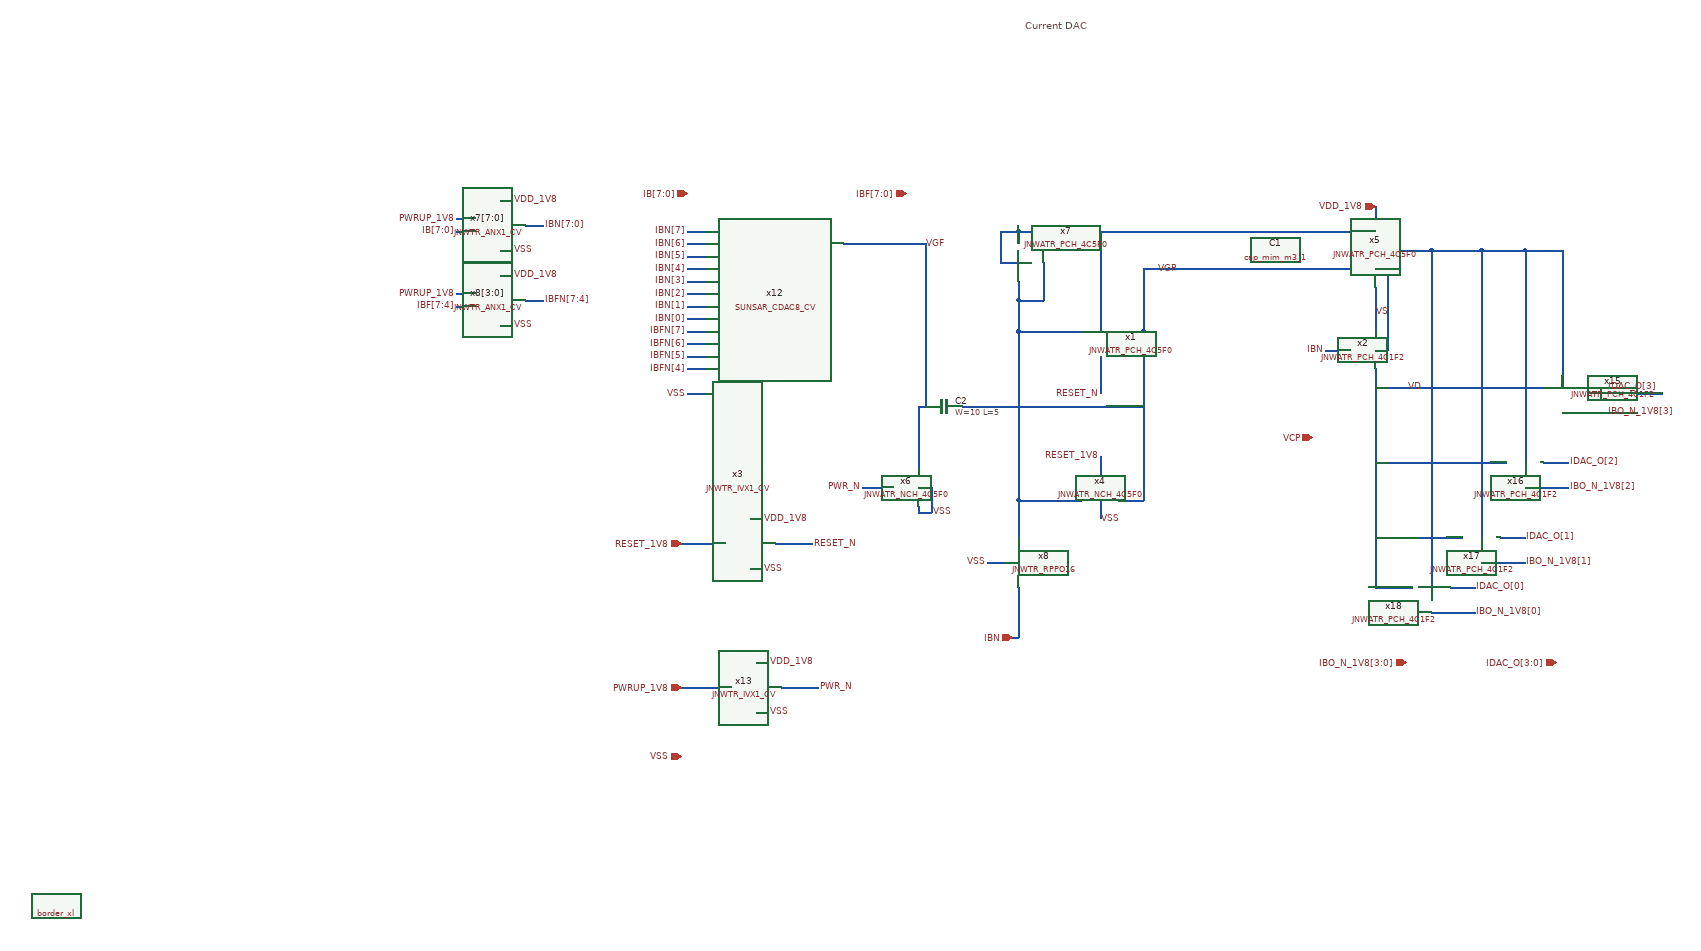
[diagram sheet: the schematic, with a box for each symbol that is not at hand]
v {xschem version=3.4.5 file_version=1.2
}
G {}
K {}
V {}
S {}
E {}
T {Current DAC} 1740 -1640 0 0 0.5 0.5 {}
N 2300 -1210 2300 -1140 {
lab=VS}
N 2300 -1110 2320 -1110 {
lab=VDD_1V8}
N 2320 -1240 2320 -1110 {
lab=VDD_1V8}
N 2300 -1240 2320 -1240 {
lab=VDD_1V8}
N 2320 -1270 2320 -1240 {
lab=VDD_1V8}
N 2300 -1270 2320 -1270 {
lab=VDD_1V8}
N 2300 -1330 2300 -1270 {
lab=VDD_1V8}
N 1930 -1240 2260 -1240 {
lab=VGP}
N 2300 -1080 2300 -900 {
lab=VD}
N 1310 -610 1330 -610 {
lab=VDD_1V8}
N 1310 -530 1330 -530 {
lab=VSS}
N 1250 -570 1270 -570 {
lab=PWRUP_1V8}
N 1190 -570 1250 -570 {
lab=PWRUP_1V8}
N 1350 -570 1410 -570 {
lab=PWR_N}
N 2390 -1270 2390 -730 {
lab=VDD_1V8}
N 2320 -1270 2390 -1270 {
lab=VDD_1V8}
N 2470 -1270 2470 -810 {
lab=VDD_1V8}
N 2390 -1270 2470 -1270 {
lab=VDD_1V8}
N 2470 -1270 2540 -1270 {
lab=VDD_1V8}
N 2600 -1270 2600 -1050 {
lab=VDD_1V8}
N 2540 -1270 2600 -1270 {
lab=VDD_1V8}
N 2300 -1050 2570 -1050 {
lab=VD}
N 2300 -900 2300 -730 {
lab=VD}
N 2300 -730 2360 -730 {
lab=VD}
N 2300 -810 2440 -810 {
lab=VD}
N 2300 -930 2510 -930 {
lab=VD}
N 2540 -1270 2540 -930 {
lab=VDD_1V8}
N 2630 -1050 2670 -1050 {
lab=IDAC_O[3]}
N 2570 -930 2610 -930 {
lab=IDAC_O[2]}
N 2500 -810 2540 -810 {
lab=IDAC_O[1]}
N 2420 -730 2460 -730 {
lab=IDAC_O[0]}
N 2390 -690 2460 -690 {
lab=IBO_N_1V8[0]}
N 2470 -770 2540 -770 {
lab=IBO_N_1V8[1]}
N 2540 -890 2610 -890 {
lab=IBO_N_1V8[2]}
N 2600 -1010 2670 -1010 {
lab=IBO_N_1V8[3]}
N 1200 -1160 1230 -1160 {
lab=IBN[0]}
N 1200 -1180 1230 -1180 {
lab=IBN[1]}
N 1200 -1200 1230 -1200 {
lab=IBN[2]}
N 1200 -1220 1230 -1220 {
lab=IBN[3]}
N 1200 -1240 1230 -1240 {
lab=IBN[4]}
N 1200 -1260 1230 -1260 {
lab=IBN[5]}
N 1200 -1280 1230 -1280 {
lab=IBN[6]}
N 1200 -1300 1230 -1300 {
lab=IBN[7]}
N 1450 -1280 1480 -1280 {
lab=VGF}
N 1200 -1040 1230 -1040 {
lab=VSS}
N 2660 -1040 2760 -1040 {
lab=IDAC_O[3]}
N 2660 -1050 2660 -1040 {
lab=IDAC_O[3]}
N 2300 -1340 2300 -1330 {
lab=VDD_1V8}
N 2220 -1110 2260 -1110 {
lab=IBN}
N 1200 -1140 1230 -1140 {
lab=IBFN[7]}
N 1200 -1120 1230 -1120 {
lab=IBFN[6]}
N 1200 -1100 1230 -1100 {
lab=IBFN[5]}
N 1200 -1080 1230 -1080 {
lab=IBFN[4]}
N 1730 -1220 1730 -1190 {
lab=#net1}
N 1730 -1190 1770 -1190 {
lab=#net1}
N 1770 -1250 1770 -1190 {
lab=#net1}
N 1700 -1250 1730 -1250 {
lab=VDD_1V8}
N 1700 -1300 1700 -1250 {
lab=VDD_1V8}
N 1700 -1300 1730 -1300 {
lab=VDD_1V8}
N 1730 -1300 1730 -1280 {
lab=VDD_1V8}
N 1730 -1300 2300 -1300 {
lab=VDD_1V8}
N 1720 -650 1730 -650 {
lab=IBN}
N 1240 -800 1260 -800 {
lab=RESET_1V8}
N 1190 -800 1240 -800 {
lab=RESET_1V8}
N 1340 -800 1400 -800 {
lab=RESET_N}
N 1860 -1300 1860 -1140 {
lab=VDD_1V8}
N 1730 -1140 1830 -1140 {
lab=#net1}
N 1890 -1140 1930 -1140 {
lab=VGP}
N 1930 -1240 1930 -1140 {
lab=VGP}
N 1860 -1100 1860 -1040 {
lab=RESET_N}
N 1300 -840 1320 -840 {
lab=VDD_1V8}
N 1300 -760 1320 -760 {
lab=VSS}
N 1860 -870 1860 -840 {
lab=VSS}
N 1890 -870 1930 -870 {
lab=VGP}
N 1930 -1140 1930 -870 {
lab=VGP}
N 1730 -870 1830 -870 {
lab=#net1}
N 1860 -940 1860 -910 {
lab=RESET_1V8}
N 1640 -1020 1930 -1020 {
lab=VGP}
N 1580 -1280 1580 -1020 {
lab=VGF}
N 1480 -1280 1580 -1280 {
lab=VGF}
N 1480 -890 1530 -890 {
lab=PWR_N}
N 1570 -1020 1570 -920 {
lab=VGF}
N 1570 -1020 1580 -1020 {
lab=VGF}
N 1570 -890 1590 -890 {
lab=VSS}
N 1590 -890 1590 -850 {
lab=VSS}
N 1570 -850 1590 -850 {
lab=VSS}
N 1570 -860 1570 -850 {
lab=VSS}
N 900 -1270 920 -1270 {
lab=VSS}
N 900 -1350 920 -1350 {
lab=VDD_1V8}
N 940 -1310 970 -1310 {
lab=IBN[7:0]}
N 830 -1300 860 -1300 {
lab=IB[7:0]}
N 900 -1150 920 -1150 {
lab=VSS}
N 900 -1230 920 -1230 {
lab=VDD_1V8}
N 940 -1190 970 -1190 {
lab=IBFN[7:4]}
N 830 -1180 860 -1180 {
lab=IBF[7:4]}
N 830 -1320 860 -1320 {
lab=PWRUP_1V8}
N 830 -1200 860 -1200 {
lab=PWRUP_1V8}
N 1730 -1140 1730 -1120 {
lab=#net1}
N 1730 -1190 1730 -1140 {
lab=#net1}
N 1730 -1120 1730 -870 {
lab=#net1}
N 1730 -870 1730 -810 {
lab=#net1}
N 1730 -730 1730 -650 {
lab=IBN}
N 1680 -770 1710 -770 {
lab=VSS}
C {devices/ipin.sym} 2300 -1340 0 0 {name=p1 lab=VDD_1V8}
C {devices/ipin.sym} 1190 -460 0 0 {name=p2 lab=VSS}
C {devices/ipin.sym} 1190 -570 0 0 {name=p3 lab=PWRUP_1V8}
C {JNW_ATR_SKY130A/JNWATR_PCH_4C5F0.sym} 2260 -1240 0 0 {name=x5}
C {JNW_ATR_SKY130A/JNWATR_PCH_4C1F2.sym} 2260 -1110 0 0 {name=x2 }
C {JNW_TR_SKY130A/JNWTR_IVX1_CV.sym} 1270 -570 0 0 {name=x13 }
C {devices/lab_wire.sym} 1330 -610 0 1 {name=p29 sig_type=std_logic lab=VDD_1V8}
C {devices/lab_wire.sym} 1330 -530 0 1 {name=p30 sig_type=std_logic lab=VSS}
C {devices/lab_wire.sym} 1410 -570 0 1 {name=p33 sig_type=std_logic lab=PWR_N}
C {devices/iopin.sym} 2590 -610 0 0 {name=p35 lab=IDAC_O[3:0]}
C {JNW_ATR_SKY130A/JNWATR_PCH_4C1F2.sym} 2600 -1010 3 0 {name=x15 }
C {JNW_ATR_SKY130A/JNWATR_PCH_4C1F2.sym} 2540 -890 3 0 {name=x16 }
C {JNW_ATR_SKY130A/JNWATR_PCH_4C1F2.sym} 2470 -770 3 0 {name=x17 }
C {JNW_ATR_SKY130A/JNWATR_PCH_4C1F2.sym} 2390 -690 3 0 {name=x18 }
C {devices/lab_wire.sym} 2460 -730 0 1 {name=p36 sig_type=std_logic lab=IDAC_O[0]}
C {devices/lab_wire.sym} 2540 -810 0 1 {name=p37 sig_type=std_logic lab=IDAC_O[1]}
C {devices/lab_wire.sym} 2610 -930 0 1 {name=p38 sig_type=std_logic lab=IDAC_O[2]}
C {devices/lab_wire.sym} 2670 -1050 0 1 {name=p39 sig_type=std_logic lab=IDAC_O[3]}
C {devices/lab_wire.sym} 2460 -690 0 1 {name=p40 sig_type=std_logic lab=IBO_N_1V8[0]}
C {devices/lab_wire.sym} 2540 -770 0 1 {name=p41 sig_type=std_logic lab=IBO_N_1V8[1]}
C {devices/lab_wire.sym} 2610 -890 0 1 {name=p42 sig_type=std_logic lab=IBO_N_1V8[2]}
C {devices/lab_wire.sym} 2670 -1010 0 1 {name=p43 sig_type=std_logic lab=IBO_N_1V8[3]}
C {devices/ipin.sym} 1200 -1360 0 0 {name=p44 lab=IB[7:0]}
C {devices/ipin.sym} 2350 -610 0 0 {name=p45 lab=IBO_N_1V8[3:0]}
C {devices/lab_wire.sym} 2300 -1170 0 1 {name=p47 sig_type=std_logic lab=VS}
C {devices/lab_wire.sym} 2350 -1050 0 1 {name=p48 sig_type=std_logic lab=VD}
C {devices/lab_wire.sym} 1950 -1240 0 1 {name=p49 sig_type=std_logic lab=VGP}
C {devices/lab_wire.sym} 1200 -1160 0 0 {name=p46 sig_type=std_logic lab=IBN[0]
}
C {devices/lab_wire.sym} 1200 -1180 0 0 {name=p66 sig_type=std_logic lab=IBN[1]
}
C {devices/lab_wire.sym} 1200 -1200 0 0 {name=p67 sig_type=std_logic lab=IBN[2]
}
C {devices/lab_wire.sym} 1200 -1220 0 0 {name=p68 sig_type=std_logic lab=IBN[3]
}
C {devices/lab_wire.sym} 1200 -1240 0 0 {name=p69 sig_type=std_logic lab=IBN[4]
}
C {devices/lab_wire.sym} 1200 -1260 0 0 {name=p70 sig_type=std_logic lab=IBN[5]
}
C {devices/lab_wire.sym} 1200 -1280 0 0 {name=p71 sig_type=std_logic lab=IBN[6]
}
C {devices/lab_wire.sym} 1200 -1300 0 0 {name=p72 sig_type=std_logic lab=IBN[7]
}
C {devices/lab_wire.sym} 1200 -1040 0 0 {name=p74 sig_type=std_logic lab=VSS
}
C {SUN_SAR9B_SKY130NM/SUNSAR_CDAC8_CV.sym} 1250 -1300 0 0 {name=x12}
C {devices/ipin.sym} 1550 -1360 0 0 {name=p124 lab=IBF[7:0]}
C {devices/lab_wire.sym} 1200 -1140 0 0 {name=p4 sig_type=std_logic lab=IBFN[7]
}
C {devices/lab_wire.sym} 1200 -1120 0 0 {name=p5 sig_type=std_logic lab=IBFN[6]
}
C {devices/lab_wire.sym} 1200 -1100 0 0 {name=p6 sig_type=std_logic lab=IBFN[5]
}
C {devices/lab_wire.sym} 1200 -1080 0 0 {name=p7 sig_type=std_logic lab=IBFN[4]
}
C {devices/ipin.sym} 1720 -650 0 0 {name=p8 lab=IBN}
C {JNW_ATR_SKY130A/JNWATR_PCH_4C5F0.sym} 1770 -1250 0 1 {name=x7}
C {JNW_ATR_SKY130A/JNWATR_PCH_4C5F0.sym} 1860 -1100 3 0 {name=x1 }
C {devices/ipin.sym} 1190 -800 0 0 {name=p9 lab=RESET_1V8}
C {devices/lab_wire.sym} 1400 -800 0 1 {name=p12 sig_type=std_logic lab=RESET_N}
C {devices/lab_wire.sym} 1860 -1040 0 0 {name=p13 sig_type=std_logic lab=RESET_N}
C {JNW_TR_SKY130A/JNWTR_IVX1_CV.sym} 1260 -800 0 0 {name=x3 }
C {devices/lab_wire.sym} 1320 -840 0 1 {name=p10 sig_type=std_logic lab=VDD_1V8}
C {devices/lab_wire.sym} 1320 -760 0 1 {name=p11 sig_type=std_logic lab=VSS}
C {JNW_ATR_SKY130A/JNWATR_NCH_4C5F0.sym} 1860 -910 3 1 {name=x4 }
C {devices/lab_wire.sym} 1860 -840 0 1 {name=p14 sig_type=std_logic lab=VSS}
C {devices/lab_wire.sym} 1860 -940 0 0 {name=p15 sig_type=std_logic lab=RESET_1V8}
C {sky130_fd_pr/cap_mim_m3_1.sym} 2140 -1270 0 0 {name=C1 model=cap_mim_m3_1 W=10 L=10 MF=2 spiceprefix=X}
C {sky130_fd_pr/cap_mim_m3_1.sym} 1610 -1020 1 0 {name=C2 model=cap_mim_m3_1 W=10 L=5 MF=1 spiceprefix=X}
C {devices/lab_wire.sym} 1480 -890 0 0 {name=p16 sig_type=std_logic lab=PWR_N}
C {JNW_ATR_SKY130A/JNWATR_NCH_4C5F0.sym} 1530 -890 0 0 {name=x6 }
C {devices/lab_wire.sym} 1590 -850 0 1 {name=p17 sig_type=std_logic lab=VSS}
C {devices/lab_wire.sym} 920 -1270 0 1 {name=p18 sig_type=std_logic lab=VSS}
C {devices/lab_wire.sym} 920 -1350 0 1 {name=p19 sig_type=std_logic lab=VDD_1V8}
C {devices/lab_wire.sym} 830 -1300 0 0 {name=p20 sig_type=std_logic lab=IB[7:0]
}
C {devices/lab_wire.sym} 970 -1310 0 1 {name=p21 sig_type=std_logic lab=IBN[7:0]
}
C {devices/lab_wire.sym} 920 -1150 0 1 {name=p22 sig_type=std_logic lab=VSS}
C {devices/lab_wire.sym} 920 -1230 0 1 {name=p23 sig_type=std_logic lab=VDD_1V8}
C {devices/lab_wire.sym} 830 -1180 0 0 {name=p24 sig_type=std_logic lab=IBF[7:4]
}
C {devices/lab_wire.sym} 970 -1190 0 1 {name=p25 sig_type=std_logic lab=IBFN[7:4]
}
C {JNW_TR_SKY130A/JNWTR_ANX1_CV.sym} 860 -1300 0 0 {name=x7[7:0]}
C {JNW_TR_SKY130A/JNWTR_ANX1_CV.sym} 860 -1180 0 0 {name=x8[3:0]}
C {devices/lab_wire.sym} 830 -1200 0 0 {name=p27 sig_type=std_logic lab=PWRUP_1V8}
C {devices/lab_wire.sym} 830 -1320 0 0 {name=p26 sig_type=std_logic lab=PWRUP_1V8}
C {devices/ipin.sym} 2200 -970 0 0 {name=p28 lab=VCP}
C {devices/lab_wire.sym} 1580 -1280 0 1 {name=p32 sig_type=std_logic lab=VGF}
C {JNW_TR_SKY130A/JNWTR_RPPO16.sym} 1730 -810 1 0 {name=x8 }
C {devices/lab_wire.sym} 1680 -770 0 0 {name=p50 sig_type=std_logic lab=VSS}
C {devices/lab_wire.sym} 2220 -1110 0 0 {name=p51 sig_type=std_logic lab=IBN}
C {cborder/border_xl.sym} 190 -220 0 0 {user="Carsten Wulff" company="Carsten Wulff Software"}
